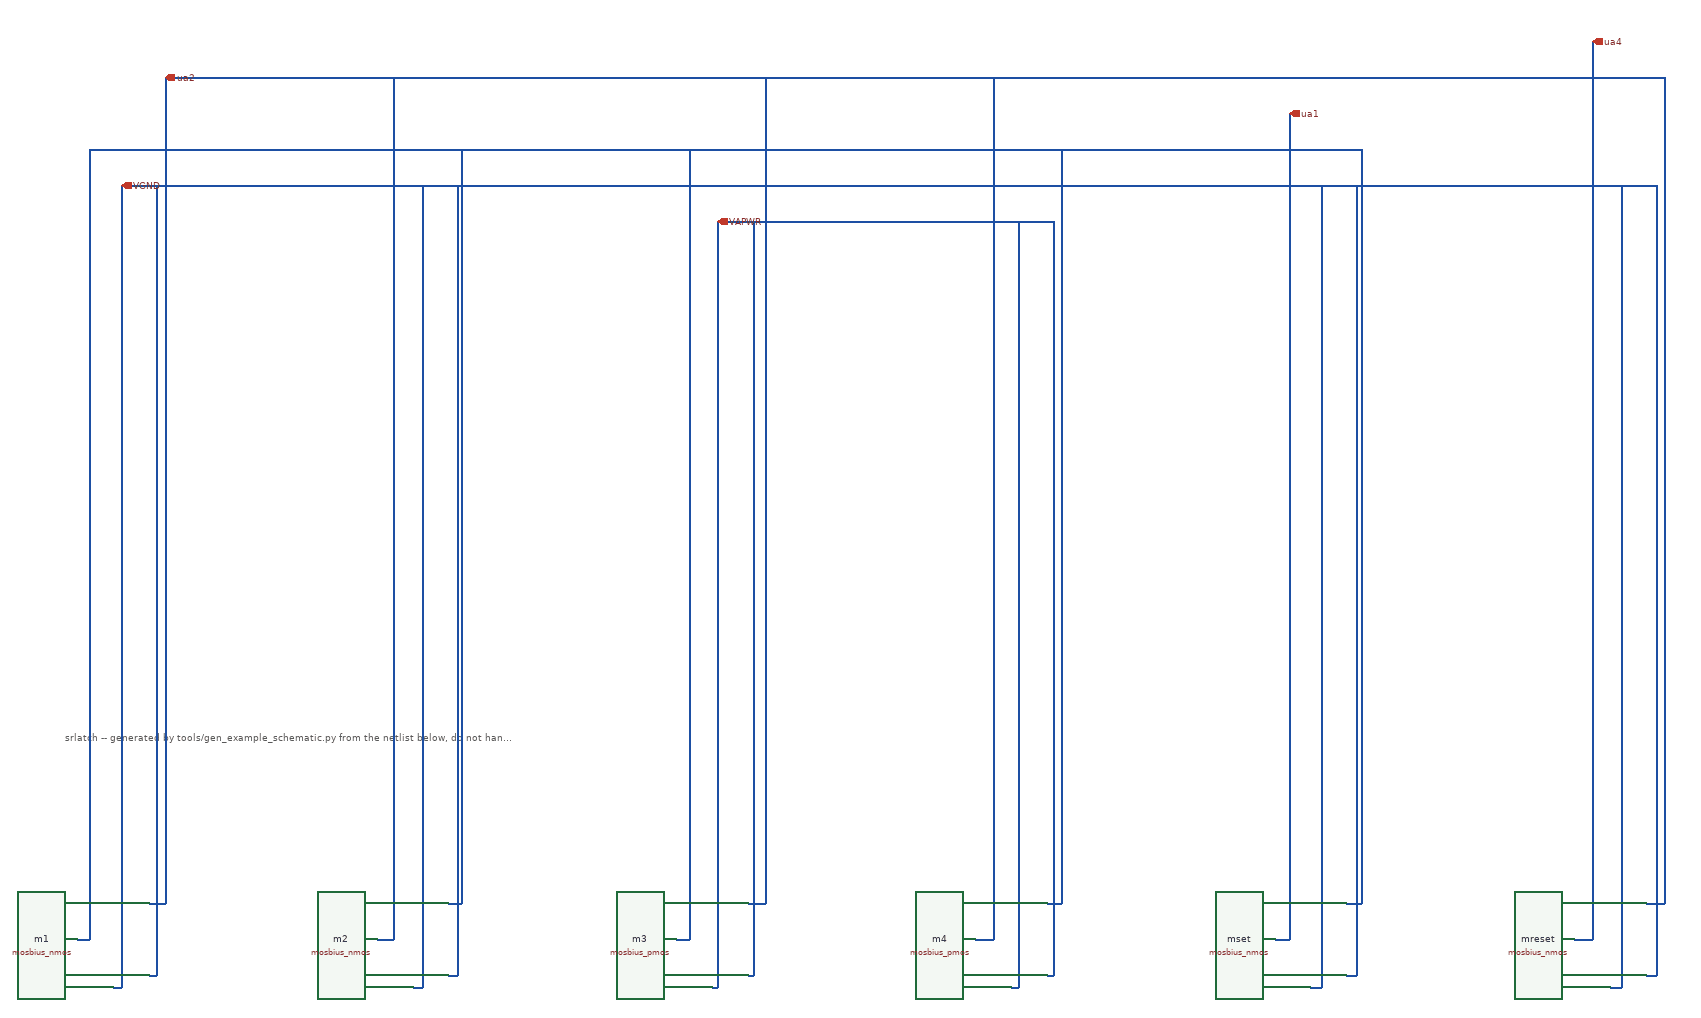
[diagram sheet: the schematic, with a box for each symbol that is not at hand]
v {xschem version=3.4.8RC file_version=1.2}
G {}
K {}
V {}
S {}
E {}
T {srlatch -- generated by tools/gen_example_schematic.py from the netlist below, do not hand-edit} -80 -350 0 0 0.25 0.25 {}
N -60 0 -40 0 {
lab=qb}
N -40 0 -40 -1320 {
lab=qb}
N 60 -60 86 -60 {
lab=ua2}
N 86 -60 86 -1440 {
lab=ua2}
N 60 60 72 60 {
lab=VGND}
N 72 60 72 -1260 {
lab=VGND}
N 0 80 13 80 {
lab=VGND}
N 13 80 13 -1260 {
lab=VGND}
N 440 0 467 0 {
lab=ua2}
N 467 0 467 -1440 {
lab=ua2}
N 560 -60 581 -60 {
lab=qb}
N 581 -60 581 -1320 {
lab=qb}
N 560 60 574 60 {
lab=VGND}
N 574 60 574 -1260 {
lab=VGND}
N 500 80 515 80 {
lab=VGND}
N 515 80 515 -1260 {
lab=VGND}
N 940 0 962 0 {
lab=qb}
N 962 0 962 -1320 {
lab=qb}
N 1060 -60 1088 -60 {
lab=ua2}
N 1088 -60 1088 -1440 {
lab=ua2}
N 1060 60 1068 60 {
lab=VAPWR}
N 1068 60 1068 -1200 {
lab=VAPWR}
N 1000 80 1009 80 {
lab=VAPWR}
N 1009 80 1009 -1200 {
lab=VAPWR}
N 1440 0 1469 0 {
lab=ua2}
N 1469 0 1469 -1440 {
lab=ua2}
N 1560 -60 1583 -60 {
lab=qb}
N 1583 -60 1583 -1320 {
lab=qb}
N 1560 60 1570 60 {
lab=VAPWR}
N 1570 60 1570 -1200 {
lab=VAPWR}
N 1500 80 1511 80 {
lab=VAPWR}
N 1511 80 1511 -1200 {
lab=VAPWR}
N 1940 0 1965 0 {
lab=ua1}
N 1965 0 1965 -1380 {
lab=ua1}
N 2060 -60 2084 -60 {
lab=qb}
N 2084 -60 2084 -1320 {
lab=qb}
N 2060 60 2076 60 {
lab=VGND}
N 2076 60 2076 -1260 {
lab=VGND}
N 2000 80 2017 80 {
lab=VGND}
N 2017 80 2017 -1260 {
lab=VGND}
N 2440 0 2471 0 {
lab=ua4}
N 2471 0 2471 -1500 {
lab=ua4}
N 2560 -60 2590 -60 {
lab=ua2}
N 2590 -60 2590 -1440 {
lab=ua2}
N 2560 60 2578 60 {
lab=VGND}
N 2578 60 2578 -1260 {
lab=VGND}
N 2500 80 2519 80 {
lab=VGND}
N 2519 80 2519 -1260 {
lab=VGND}
N -40 -1320 2084 -1320 {
lab=qb}
N 86 -1440 2590 -1440 {
lab=ua2}
C {devices/iopin.sym} 86 -1440 0 1 {name=port_ua2 lab=ua2}
N 13 -1260 2578 -1260 {
lab=VGND}
C {devices/iopin.sym} 13 -1260 0 1 {name=port_VGND lab=VGND}
N 1009 -1200 1570 -1200 {
lab=VAPWR}
C {devices/iopin.sym} 1009 -1200 0 1 {name=port_VAPWR lab=VAPWR}
C {devices/iopin.sym} 1965 -1380 0 1 {name=port_ua1 lab=ua1}
C {devices/iopin.sym} 2471 -1500 0 1 {name=port_ua4 lab=ua4}
C {mosbius_nmos.sym} 0 0 0 0 {name=m1 w=2}
C {mosbius_nmos.sym} 500 0 0 0 {name=m2 w=2}
C {mosbius_pmos.sym} 1000 0 0 0 {name=m3 w=2}
C {mosbius_pmos.sym} 1500 0 0 0 {name=m4 w=2}
C {mosbius_nmos.sym} 2000 0 0 0 {name=mset w=2}
C {mosbius_nmos.sym} 2500 0 0 0 {name=mreset w=2}
